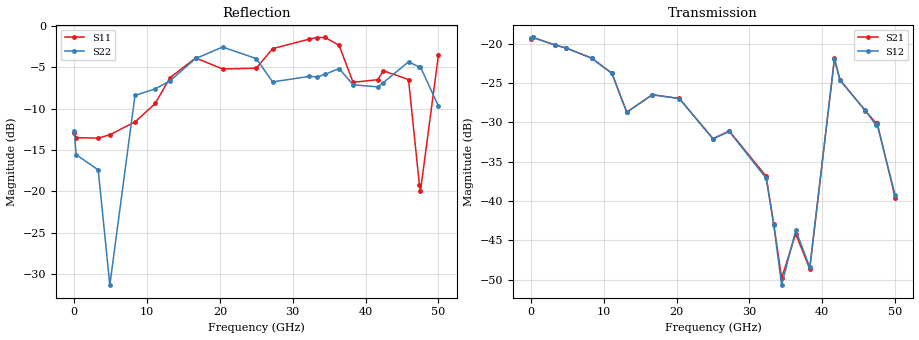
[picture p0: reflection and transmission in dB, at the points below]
!Keysight Technologies,N5245B,MY58422270,A.16.20.02
!Date: Thursday, March 05, 2026 01:21:18
!Correction: S11(C  2-Port  )
!S21(C  2-Port  )
!S12(C  2-Port  )
!S22(C  2-Port  )
!S2P File: Measurements: S11, S21, S12, S22:
# Hz S  dB  R 50
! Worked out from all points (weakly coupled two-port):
!   3201 points, 10 MHz to 50 GHz, reference 50 ohm
!   highest |S21| = -19.19 dB at 275.6 MHz (marker M1); lowest = -49.8 dB at 34.42 GHz (marker M2)
!   lowest |S11| = -20.0 dB at 47.53 GHz (marker M3), VSWR 1.22, Z = 46.1 + j8.86 ohm
!   |S11| at or under -10 dB: start of sweep to 10.14 GHz; 11.36 GHz to 11.92 GHz (566.5 MHz wide, 4.87 % of centre); 46.66 GHz to 48.28 GHz (1.629 GHz wide, 3.43 % of centre)
!   |S22| runs from -31.3 to -2.5 dB; largest |S21 - S12| = 0.0027
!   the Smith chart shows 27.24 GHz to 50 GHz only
!   S11 on the Smith chart (normalised r, x): 27.24 GHz: 0.18, +0.37; 32.3 GHz: 0.42, +1.86; 36.36 GHz: 2.40, -3.37; 42.44 GHz: 1.00, -1.27; 47.39 GHz: 0.84, +0.12; 50 GHz: 0.61, -1.34
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1e7  -12.95 -4.0  -19.34 3.8  -19.30 5.2  -12.67 31.4
2.755719e8  -13.52 -11.8  -19.19 -10.5  -19.19 -10.9  -15.57 -14.1
3.306216e9  -13.57 -88.0  -20.15 -127.3  -20.16 -127.3  -17.41 -148.7
4.899647e9  -13.16 -122.1  -20.56 169.5  -20.56 169.5  -31.33 -124.0
8.352081e9  -11.62 174.7  -21.84 25.8  -21.82 25.7  -8.41 -152.0
1.113278e10  -9.38 107.7  -23.75 -82.3  -23.77 -82.3  -7.62 93.9
1.316362e10  -6.26 64.3  -28.70 -142.9  -28.72 -143.3  -6.64 -17.3
1.667854e10  -3.89 -43.8  -26.49 156.4  -26.49 156.3  -3.95 -139.3
2.038092e10  -5.22 -121.1  -26.96 40.2  -26.98 39.7  -2.57 156.0
2.5005e10  -5.12 179.7  -32.06 -64.5  -32.11 -65.1  -3.96 71.5
2.723893e10  -2.76 138.6  -31.10 -114.6  -31.16 -114.6  -6.78 31.4
3.230042e10  -1.60 54.7  -36.87 49.0  -37.11 51.0  -6.11 -103.1
3.334708e10  -1.42 36.1  -42.98 3.2  -43.07 2.7  -6.17 -125.8
3.442499e10  -1.40 16.8  -49.81 -98.9  -50.71 -102.4  -5.87 -148.5
3.63621e10  -2.36 -22.7  -44.18 111.7  -43.71 108.7  -5.16 175.0
3.828359e10  -6.83 -22.2  -48.67 105.7  -48.44 93.0  -7.12 139.5
4.167354e10  -6.51 -52.5  -21.87 -59.6  -21.98 -60.4  -7.38 118.2
4.243901e10  -5.44 -57.5  -24.60 -120.2  -24.65 -120.1  -6.86 113.7
4.589145e10  -6.49 -117.3  -28.50 55.6  -28.47 55.5  -4.35 62.8
4.739115e10  -19.27 140.8  -30.10 2.7  -30.38 1.4  -4.99 42.2
4.753174e10  -19.98 108.4  -30.06 -0.2  -30.25 -0.2  -4.98 40.6
5e10  -3.53 -66.3  -39.57 -129.8  -39.26 -129.6  -9.71 3.1
